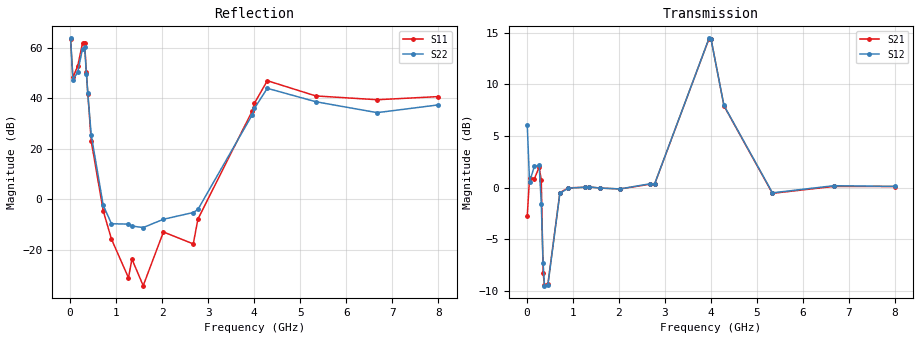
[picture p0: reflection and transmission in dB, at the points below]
!Agilent Technologies,N5230A,US43500312,A.07.50.67
!Agilent N5230A: A.07.50.67
!Date: Tuesday, June 09, 2015 15:37:00
!Correction: S11(Full 2 Port(1,2))
!S21(Full 2 Port(1,2))
!S12(Full 2 Port(1,2))
!S22(Full 2 Port(1,2))
!S2P File: Measurements: S11, S21, S12, S22:
# Hz S  MA  R 50
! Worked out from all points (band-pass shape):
!   1601 points, 10 MHz to 8 GHz, reference 50 ohm
!   highest |S21| = 14.42 dB at 3.96 GHz (marker M1); lowest = -9.5 dB at 384.5 MHz (marker M2)
!   |S21| within 3 dB of the highest: 3.748 GHz to 4.202 GHz (454.4 MHz wide, 11.4 % of centre)
!   lowest |S11| = -34.3 dB at 1.588 GHz (marker M3), VSWR 1.04, Z = 48.8 - j1.5 ohm
!   |S11| at or under -10 dB: 831.3 MHz to 2.108 GHz (1.276 GHz wide, 86.9 % of centre); 2.521 GHz to 2.747 GHz (226.4 MHz wide, 8.59 % of centre); 3.253 GHz to 3.335 GHz (81.58 MHz wide, 2.48 % of centre)
!   |S22| runs from -13.7 to 63.6 dB; largest |S21 - S12| = 1.8
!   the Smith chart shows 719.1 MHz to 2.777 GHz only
!   S11 on the Smith chart (normalised r, x): 719.1 MHz: 0.26, -0.00; 898.9 MHz: 0.91, -0.30; 1.268 GHz: 1.04, +0.03; 2.027 GHz: 0.68, -0.20; 2.777 GHz: 2.33, -0.14
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1e7  1496 171.2  0.7253 61.5  2.016 2.7  1520 -19.4
5.99375e7  255.6 327.2  1.116 0.6  1.066 -2.5  229.6 92.6
1.648062e8  429.4 404.8  1.103 7.8  1.267 3.0  325.9 126.2
2.69675e8  1219 390.7  1.258 9.5  1.279 3.2  950.7 106.9
3.146188e8  1216 429.8  1.087 38.4  0.8369 30.9  1014 151.2
3.545688e8  322.3 450.4  0.3878 37.0  0.4313 37.5  296.5 180.9
3.845312e8  122.7 448.1  0.3364 28.8  0.335 24.3  123.5 188.3
4.594375e8  13.95 439.8  0.343 31.2  0.3376 32.0  18.43 218.3
7.191125e8  0.5862 540.1  0.9446 52.9  0.9374 52.9  0.754 443.2
8.988875e8  0.1603 621.8  0.9966 48.0  0.9937 47.8  0.3237 536.7
1.268425e9  0.02758 756.5  1.004 49.1  1.004 49.2  0.3193 720.7
1.343331e9  0.06464 868.1  1.008 49.3  1.008 49.4  0.2917 762.4
1.588025e9  0.01924 952.7  0.9949 48.7  0.9942 48.7  0.2725 859.6
2.027475e9  0.2228 939.5  0.9845 46.1  0.9855 46.3  0.3975 1056.6
2.676662e9  0.1294 1038.0  1.038 51.9  1.043 51.9  0.5414 1219.3
2.776538e9  0.4005 1076.3  1.037 51.7  1.04 51.8  0.6221 1257.9
3.960056e9  55.98 1063.9  5.26 35.6  5.276 35.8  47.1 1532.4
4.005e9  78.72 1059.4  5.211 24.8  5.219 24.9  62.49 1527.3
4.28465e9  220.7 995.6  2.486 -42.3  2.497 -41.8  156 1458.6
5.338331e9  110.1 971.7  0.9379 8.0  0.9432 7.9  84.51 1405.7
6.671662e9  92.65 1005.2  1.013 6.7  1.021 7.2  51.39 1345.3
8e9  106.8 1030.5  1.012 5.0  1.013 5.4  73.14 1311.2
